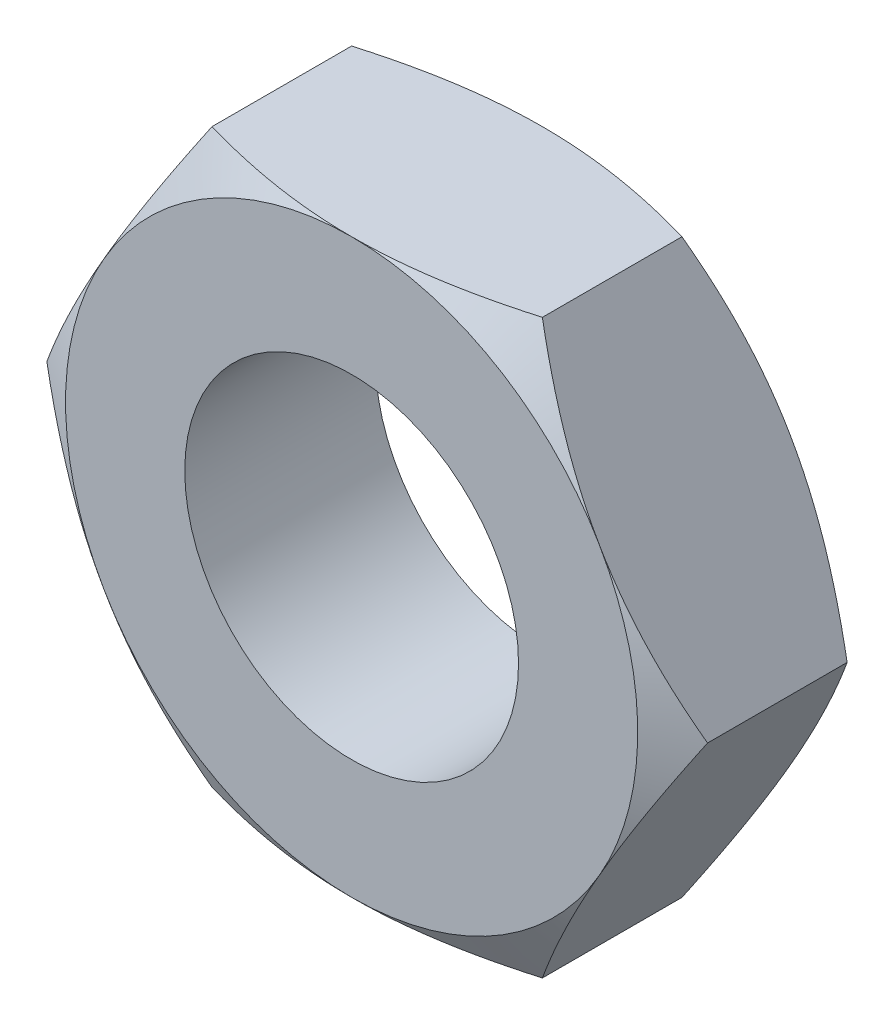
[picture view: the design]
ISO-10303-21;
HEADER;
FILE_DESCRIPTION(('STEP AP214'),'2;1');
FILE_NAME('part.step','',(''),(''),'','','');
FILE_SCHEMA(('AUTOMOTIVE_DESIGN { 1 0 10303 214 1 1 1 1 }'));
ENDSEC;
DATA;
#1=APPLICATION_CONTEXT('core data for automotive mechanical design processes');
#2=APPLICATION_PROTOCOL_DEFINITION('international standard','automotive_design',2000,#1);
#3=PRODUCT_CONTEXT('',#1,'mechanical');
#4=PRODUCT('Part','Part','',(#3));
#5=PRODUCT_RELATED_PRODUCT_CATEGORY('part','',(#4));
#6=PRODUCT_DEFINITION_FORMATION('','',#4);
#7=PRODUCT_DEFINITION_CONTEXT('part definition',#1,'design');
#8=PRODUCT_DEFINITION('design','',#6,#7);
#9=PRODUCT_DEFINITION_SHAPE('','',#8);
#10=(LENGTH_UNIT() NAMED_UNIT(*) SI_UNIT(.MILLI.,.METRE.));
#11=(NAMED_UNIT(*) PLANE_ANGLE_UNIT() SI_UNIT($,.RADIAN.));
#12=(NAMED_UNIT(*) SI_UNIT($,.STERADIAN.) SOLID_ANGLE_UNIT());
#13=UNCERTAINTY_MEASURE_WITH_UNIT(LENGTH_MEASURE(1.E-05),#10,'distance_accuracy_value','');
#14=(GEOMETRIC_REPRESENTATION_CONTEXT(3) GLOBAL_UNCERTAINTY_ASSIGNED_CONTEXT((#13)) GLOBAL_UNIT_ASSIGNED_CONTEXT((#10,
#11,#12)) REPRESENTATION_CONTEXT('',''));
#15=CARTESIAN_POINT('',(0.,0.,0.));
#16=DIRECTION('',(0.,0.,1.));
#17=DIRECTION('',(1.,0.,0.));
#18=AXIS2_PLACEMENT_3D('',#15,#16,#17);
#19=CARTESIAN_POINT('',(13.856406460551,0.,4.));
#20=DIRECTION('',(-0.866025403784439,-0.5,0.));
#21=DIRECTION('',(0.5,-0.866025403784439,0.));
#22=AXIS2_PLACEMENT_3D('',#19,#20,#21);
#23=PLANE('',#22);
#24=CARTESIAN_POINT('',(6.92808776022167,12.0002,-2.92813656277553));
#25=CARTESIAN_POINT('',(7.08038456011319,11.7364142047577,-3.01605036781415));
#26=CARTESIAN_POINT('',(7.23324920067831,11.4716448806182,-3.09997400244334));
#27=CARTESIAN_POINT('',(7.54020434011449,10.9399829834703,-3.25873378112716));
#28=CARTESIAN_POINT('',(7.69429522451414,10.6730897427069,-3.33356693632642));
#29=CARTESIAN_POINT('',(8.15905073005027,9.86810959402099,-3.54298246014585));
#30=CARTESIAN_POINT('',(8.47155003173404,9.3268449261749,-3.66209676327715));
#31=CARTESIAN_POINT('',(8.93919090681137,8.51686717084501,-3.80176893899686));
#32=CARTESIAN_POINT('',(9.09293539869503,8.25057389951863,-3.84155620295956));
#33=CARTESIAN_POINT('',(9.40113622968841,7.71675440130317,-3.90827663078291));
#34=CARTESIAN_POINT('',(9.55559258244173,7.44922815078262,-3.93520954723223));
#35=CARTESIAN_POINT('',(9.86476279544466,6.91372963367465,-3.97553140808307));
#36=CARTESIAN_POINT('',(10.0194761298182,6.64575827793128,-3.98893644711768));
#37=CARTESIAN_POINT('',(10.3290461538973,6.10956726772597,-4.00191690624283));
#38=CARTESIAN_POINT('',(10.4839028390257,5.84134762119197,-4.00149275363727));
#39=CARTESIAN_POINT('',(10.7734076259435,5.3399106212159,-3.98777998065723));
#40=CARTESIAN_POINT('',(10.908076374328,5.10665750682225,-3.97616401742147));
#41=CARTESIAN_POINT('',(11.1771041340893,4.64068775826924,-3.94269199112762));
#42=CARTESIAN_POINT('',(11.3114631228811,4.40797116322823,-3.92083520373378));
#43=CARTESIAN_POINT('',(11.5797983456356,3.94320092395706,-3.86726258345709));
#44=CARTESIAN_POINT('',(11.7137741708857,3.711147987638,-3.83553860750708));
#45=CARTESIAN_POINT('',(11.9810977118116,3.24813003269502,-3.76278822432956));
#46=CARTESIAN_POINT('',(12.1144453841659,3.01716508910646,-3.7217611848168));
#47=CARTESIAN_POINT('',(12.5192297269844,2.31605804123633,-3.5836883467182));
#48=CARTESIAN_POINT('',(12.789494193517,1.84794625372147,-3.47287511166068));
#49=CARTESIAN_POINT('',(13.3259930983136,0.918702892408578,-3.22137423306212));
#50=CARTESIAN_POINT('',(13.5922344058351,0.457559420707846,-3.08074565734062));
#51=CARTESIAN_POINT('',(13.8565219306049,-0.000200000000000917,-2.92813656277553));
#52=B_SPLINE_CURVE_WITH_KNOTS('',3,(#24,#25,#26,#27,#28,#29,#30,#31,#32,#33,#34,#35,#36,#37,#38,
#39,#40,#41,#42,#43,#44,#45,#46,#47,#48,#49,#50,#51),.UNSPECIFIED.,.F.,.F.,(4,2,2,2,2,2,2,2,2,2,
2,2,2,4),(0.,0.951004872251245,1.90232158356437,3.80900466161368,4.7389455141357,
5.66890426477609,6.59775529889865,7.52657763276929,8.33514643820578,9.14377244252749,
9.95306755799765,10.7624176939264,12.4167102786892,14.0677556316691),.UNSPECIFIED.);
#53=CARTESIAN_POINT('',(6.92820323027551,12.,-2.92820323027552));
#54=VERTEX_POINT('',#53);
#55=CARTESIAN_POINT('',(10.3923048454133,6.,-4.));
#56=VERTEX_POINT('',#55);
#57=EDGE_CURVE('E127',#54,#56,#52,.T.);
#58=ORIENTED_EDGE('',*,*,#57,.F.);
#59=DIRECTION('',(0.,0.,-1.));
#60=VECTOR('',#59,1.);
#61=CARTESIAN_POINT('',(6.92820323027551,12.,4.));
#62=LINE('',#61,#60);
#63=CARTESIAN_POINT('',(6.92820323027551,12.,2.92820323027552));
#64=VERTEX_POINT('',#63);
#65=EDGE_CURVE('E264',#64,#54,#62,.T.);
#66=ORIENTED_EDGE('',*,*,#65,.F.);
#67=CARTESIAN_POINT('',(13.8565219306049,-0.000200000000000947,2.92813656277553));
#68=CARTESIAN_POINT('',(13.7042251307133,0.263585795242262,3.01605036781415));
#69=CARTESIAN_POINT('',(13.5513604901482,0.528355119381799,3.09997400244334));
#70=CARTESIAN_POINT('',(13.244405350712,1.06001701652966,3.25873378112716));
#71=CARTESIAN_POINT('',(13.0903144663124,1.32691025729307,3.33356693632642));
#72=CARTESIAN_POINT('',(12.6255589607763,2.13189040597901,3.54298246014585));
#73=CARTESIAN_POINT('',(12.3130596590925,2.6731550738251,3.66209676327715));
#74=CARTESIAN_POINT('',(11.8454187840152,3.48313282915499,3.80176893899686));
#75=CARTESIAN_POINT('',(11.6916742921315,3.74942610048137,3.84155620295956));
#76=CARTESIAN_POINT('',(11.3834734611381,4.28324559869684,3.90827663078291));
#77=CARTESIAN_POINT('',(11.2290171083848,4.55077184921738,3.93520954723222));
#78=CARTESIAN_POINT('',(10.9198468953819,5.08627036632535,3.97553140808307));
#79=CARTESIAN_POINT('',(10.7651335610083,5.35424172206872,3.98893644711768));
#80=CARTESIAN_POINT('',(10.4555635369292,5.89043273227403,4.00191690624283));
#81=CARTESIAN_POINT('',(10.3007068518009,6.15865237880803,4.00149275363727));
#82=CARTESIAN_POINT('',(10.0112020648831,6.6600893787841,3.98777998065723));
#83=CARTESIAN_POINT('',(9.87653331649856,6.89334249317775,3.97616401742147));
#84=CARTESIAN_POINT('',(9.60750555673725,7.35931224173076,3.94269199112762));
#85=CARTESIAN_POINT('',(9.47314656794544,7.59202883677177,3.92083520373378));
#86=CARTESIAN_POINT('',(9.2048113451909,8.05679907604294,3.86726258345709));
#87=CARTESIAN_POINT('',(9.07083551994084,8.288852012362,3.83553860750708));
#88=CARTESIAN_POINT('',(8.80351197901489,8.75186996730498,3.76278822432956));
#89=CARTESIAN_POINT('',(8.67016430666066,8.98283491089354,3.7217611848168));
#90=CARTESIAN_POINT('',(8.2653799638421,9.68394195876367,3.5836883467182));
#91=CARTESIAN_POINT('',(7.99511549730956,10.1520537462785,3.47287511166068));
#92=CARTESIAN_POINT('',(7.45861659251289,11.0812971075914,3.22137423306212));
#93=CARTESIAN_POINT('',(7.19237528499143,11.5424405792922,3.08074565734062));
#94=CARTESIAN_POINT('',(6.92808776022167,12.0002,2.92813656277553));
#95=B_SPLINE_CURVE_WITH_KNOTS('',3,(#67,#68,#69,#70,#71,#72,#73,#74,#75,#76,#77,#78,#79,#80,#81,
#82,#83,#84,#85,#86,#87,#88,#89,#90,#91,#92,#93,#94),.UNSPECIFIED.,.F.,.F.,(4,2,2,2,2,2,2,2,2,2,
2,2,2,4),(0.,0.951004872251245,1.90232158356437,3.80900466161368,4.7389455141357,
5.66890426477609,6.59775529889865,7.5265776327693,8.33514643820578,9.14377244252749,
9.95306755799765,10.7624176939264,12.4167102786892,14.0677556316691),.UNSPECIFIED.);
#96=CARTESIAN_POINT('',(10.3923048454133,6.,4.));
#97=VERTEX_POINT('',#96);
#98=EDGE_CURVE('E240',#97,#64,#95,.T.);
#99=ORIENTED_EDGE('',*,*,#98,.F.);
#100=CARTESIAN_POINT('',(13.856406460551,0.,2.92820323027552));
#101=VERTEX_POINT('',#100);
#102=EDGE_CURVE('E246',#101,#97,#95,.T.);
#103=ORIENTED_EDGE('',*,*,#102,.F.);
#104=DIRECTION('',(0.,0.,-1.));
#105=VECTOR('',#104,1.);
#106=CARTESIAN_POINT('',(13.856406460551,0.,4.));
#107=LINE('',#106,#105);
#108=CARTESIAN_POINT('',(13.856406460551,0.,-2.92820323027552));
#109=VERTEX_POINT('',#108);
#110=EDGE_CURVE('E163',#101,#109,#107,.T.);
#111=ORIENTED_EDGE('',*,*,#110,.T.);
#112=EDGE_CURVE('E141',#56,#109,#52,.T.);
#113=ORIENTED_EDGE('',*,*,#112,.F.);
#114=EDGE_LOOP('',(#58,#66,#99,#103,#111,#113));
#115=FACE_BOUND('',#114,.T.);
#116=ADVANCED_FACE('F37',(#115),#23,.F.);
#117=CARTESIAN_POINT('',(6.92820323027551,12.,4.));
#118=DIRECTION('',(0.,-1.,0.));
#119=DIRECTION('',(1.,0.,0.));
#120=AXIS2_PLACEMENT_3D('',#117,#118,#119);
#121=PLANE('',#120);
#122=CARTESIAN_POINT('',(-18.7085127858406,12.,1.90415756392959));
#123=CARTESIAN_POINT('',(-18.4460090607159,12.,1.77659054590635));
#124=CARTESIAN_POINT('',(-18.1831999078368,12.,1.64965232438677));
#125=CARTESIAN_POINT('',(-17.6569070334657,12.,1.39717571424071));
#126=CARTESIAN_POINT('',(-17.3934233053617,12.,1.27163733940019));
#127=CARTESIAN_POINT('',(-16.6017958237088,12.,0.897302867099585));
#128=CARTESIAN_POINT('',(-16.0725519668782,12.,0.650824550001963));
#129=CARTESIAN_POINT('',(-15.007722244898,12.,0.164215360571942));
#130=CARTESIAN_POINT('',(-14.4721175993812,12.,-0.0758745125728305));
#131=CARTESIAN_POINT('',(-13.3966823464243,12.,-0.546361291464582));
#132=CARTESIAN_POINT('',(-12.8568519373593,12.,-0.776758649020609));
#133=CARTESIAN_POINT('',(-11.7544580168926,12.,-1.23259581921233));
#134=CARTESIAN_POINT('',(-11.1917261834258,12.,-1.45763065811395));
#135=CARTESIAN_POINT('',(-10.0597119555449,12.,-1.8909069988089));
#136=CARTESIAN_POINT('',(-9.49042883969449,12.,-2.09914663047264));
#137=CARTESIAN_POINT('',(-8.34545795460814,12.,-2.49343583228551));
#138=CARTESIAN_POINT('',(-7.76978547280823,12.,-2.67952944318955));
#139=CARTESIAN_POINT('',(-6.61012992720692,12.,-3.023632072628));
#140=CARTESIAN_POINT('',(-6.02614951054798,12.,-3.1816498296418));
#141=CARTESIAN_POINT('',(-5.14541828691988,12.,-3.3915280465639));
#142=CARTESIAN_POINT('',(-4.85184995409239,12.,-3.45682212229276));
#143=CARTESIAN_POINT('',(-4.26268919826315,12.,-3.57758690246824));
#144=CARTESIAN_POINT('',(-3.96709681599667,12.,-3.63305780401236));
#145=CARTESIAN_POINT('',(-3.37408559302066,12.,-3.73320305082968));
#146=CARTESIAN_POINT('',(-3.07666678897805,12.,-3.77787761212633));
#147=CARTESIAN_POINT('',(-2.48030879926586,12.,-3.85554301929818));
#148=CARTESIAN_POINT('',(-2.18136967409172,12.,-3.88853432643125));
#149=CARTESIAN_POINT('',(-1.58633736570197,12.,-3.94175838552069));
#150=CARTESIAN_POINT('',(-1.29025885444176,12.,-3.96215415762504));
#151=CARTESIAN_POINT('',(-0.697504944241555,12.,-3.99040145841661));
#152=CARTESIAN_POINT('',(-0.400829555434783,12.,-3.9982531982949));
#153=CARTESIAN_POINT('',(0.192590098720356,12.,-4.00122522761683));
#154=CARTESIAN_POINT('',(0.489334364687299,12.,-3.99634539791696));
#155=CARTESIAN_POINT('',(1.08235044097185,12.,-3.97397458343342));
#156=CARTESIAN_POINT('',(1.37862222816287,12.,-3.95648299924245));
#157=CARTESIAN_POINT('',(2.08755229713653,12.,-3.89991202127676));
#158=CARTESIAN_POINT('',(2.49975691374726,12.,-3.85502143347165));
#159=CARTESIAN_POINT('',(3.32115295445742,12.,-3.74325294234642));
#160=CARTESIAN_POINT('',(3.73034397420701,12.,-3.676372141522));
#161=CARTESIAN_POINT('',(4.95289147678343,12.,-3.44628715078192));
#162=CARTESIAN_POINT('',(5.76078996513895,12.,-3.25367949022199));
#163=CARTESIAN_POINT('',(6.96921318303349,12.,-2.91902105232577));
#164=CARTESIAN_POINT('',(7.37598411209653,12.,-2.79822311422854));
#165=CARTESIAN_POINT('',(8.18557519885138,12.,-2.54392558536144));
#166=CARTESIAN_POINT('',(8.58839532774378,12.,-2.41042590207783));
#167=CARTESIAN_POINT('',(9.39021237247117,12.,-2.13288017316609));
#168=CARTESIAN_POINT('',(9.78921043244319,12.,-1.98883740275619));
#169=CARTESIAN_POINT('',(10.5838863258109,12.,-1.69191619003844));
#170=CARTESIAN_POINT('',(10.9795642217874,12.,-1.53903791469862));
#171=CARTESIAN_POINT('',(12.0030149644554,12.,-1.13257010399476));
#172=CARTESIAN_POINT('',(12.6285198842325,12.,-0.873276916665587));
#173=CARTESIAN_POINT('',(13.8734735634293,12.,-0.340490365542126));
#174=CARTESIAN_POINT('',(14.4929217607,12.,-0.0669956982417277));
#175=CARTESIAN_POINT('',(15.7270740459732,12.,0.490985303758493));
#176=CARTESIAN_POINT('',(16.3417765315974,12.,0.775475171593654));
#177=CARTESIAN_POINT('',(17.5671457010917,12.,1.35294000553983));
#178=CARTESIAN_POINT('',(18.1778125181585,12.,1.6459146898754));
#179=CARTESIAN_POINT('',(19.3967367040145,12.,2.23899938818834));
#180=CARTESIAN_POINT('',(20.0049894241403,12.,2.53911893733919));
#181=CARTESIAN_POINT('',(21.218803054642,12.,3.14475459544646));
#182=CARTESIAN_POINT('',(21.8243639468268,12.,3.45027074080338));
#183=CARTESIAN_POINT('',(23.0331444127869,12.,4.06562299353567));
#184=CARTESIAN_POINT('',(23.636364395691,12.,4.37545829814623));
#185=CARTESIAN_POINT('',(24.8409400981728,12.,4.99872415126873));
#186=CARTESIAN_POINT('',(25.4422958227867,12.,5.31215469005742));
#187=CARTESIAN_POINT('',(27.1254633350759,12.,6.19473158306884));
#188=CARTESIAN_POINT('',(28.2055235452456,12.,6.7672178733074));
#189=CARTESIAN_POINT('',(30.3619311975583,12.,7.91925803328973));
#190=CARTESIAN_POINT('',(31.4382784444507,12.,8.49881226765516));
#191=CARTESIAN_POINT('',(33.584834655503,12.,9.66146627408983));
#192=CARTESIAN_POINT('',(34.6550523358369,12.,10.2445499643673));
#193=CARTESIAN_POINT('',(36.2586680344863,12.,11.1222102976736));
#194=CARTESIAN_POINT('',(36.7929031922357,12.,11.4152594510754));
#195=CARTESIAN_POINT('',(37.8608740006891,12.,12.0022649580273));
#196=CARTESIAN_POINT('',(38.3946096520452,12.,12.2962213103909));
#197=CARTESIAN_POINT('',(38.9281254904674,12.,12.5905761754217));
#198=B_SPLINE_CURVE_WITH_KNOTS('',3,(#122,#123,#124,#125,#126,#127,#128,#129,#130,#131,#132,
#133,#134,#135,#136,#137,#138,#139,#140,#141,#142,#143,#144,#145,#146,#147,#148,#149,#150,#151,
#152,#153,#154,#155,#156,#157,#158,#159,#160,#161,#162,#163,#164,#165,#166,#167,#168,#169,#170,
#171,#172,#173,#174,#175,#176,#177,#178,#179,#180,#181,#182,#183,#184,#185,#186,#187,#188,#189,
#190,#191,#192,#193,#194,#195,#196,#197),.UNSPECIFIED.,.F.,.F.,(4,2,2,2,2,2,2,2,2,2,2,2,2,2,2,2,
2,2,2,2,2,2,2,2,2,2,2,2,2,2,2,2,2,2,2,2,2,4),(0.,0.875574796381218,1.7511582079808,
3.50257929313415,5.2633676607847,7.02407385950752,8.84204683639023,10.6602219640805,
12.4747187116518,14.2886497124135,15.190737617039,16.0928074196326,16.9948591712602,
17.8968753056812,18.7869578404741,19.6770253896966,20.5671012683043,21.4572194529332,
22.7004447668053,23.9438339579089,26.4319090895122,27.7047859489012,28.9776720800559,
30.2501644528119,31.5226327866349,33.5537333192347,35.5850206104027,37.6169661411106,
39.648844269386,41.6836056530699,43.7183807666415,45.7527826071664,47.7871789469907,
51.4543492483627,55.1217095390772,58.7779483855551,60.6059425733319,62.4339343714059),.UNSPECIFIED.);
#199=CARTESIAN_POINT('',(-6.92820323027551,12.,-2.92820323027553));
#200=VERTEX_POINT('',#199);
#201=CARTESIAN_POINT('',(0.,12.,-4.));
#202=VERTEX_POINT('',#201);
#203=EDGE_CURVE('E53',#200,#202,#198,.T.);
#204=ORIENTED_EDGE('',*,*,#203,.F.);
#205=DIRECTION('',(0.,0.,-1.));
#206=VECTOR('',#205,1.);
#207=CARTESIAN_POINT('',(-6.92820323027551,12.,4.));
#208=LINE('',#207,#206);
#209=CARTESIAN_POINT('',(-6.92820323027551,12.,2.92820323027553));
#210=VERTEX_POINT('',#209);
#211=EDGE_CURVE('E260',#210,#200,#208,.T.);
#212=ORIENTED_EDGE('',*,*,#211,.F.);
#213=CARTESIAN_POINT('',(-18.7085127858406,12.,-1.90415756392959));
#214=CARTESIAN_POINT('',(-18.4460090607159,12.,-1.77659054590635));
#215=CARTESIAN_POINT('',(-18.1831999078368,12.,-1.64965232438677));
#216=CARTESIAN_POINT('',(-17.6569070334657,12.,-1.39717571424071));
#217=CARTESIAN_POINT('',(-17.3934233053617,12.,-1.27163733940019));
#218=CARTESIAN_POINT('',(-16.6017958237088,12.,-0.897302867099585));
#219=CARTESIAN_POINT('',(-16.0725519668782,12.,-0.650824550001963));
#220=CARTESIAN_POINT('',(-15.007722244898,12.,-0.164215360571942));
#221=CARTESIAN_POINT('',(-14.4721175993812,12.,0.0758745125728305));
#222=CARTESIAN_POINT('',(-13.3966823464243,12.,0.546361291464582));
#223=CARTESIAN_POINT('',(-12.8568519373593,12.,0.776758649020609));
#224=CARTESIAN_POINT('',(-11.7544580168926,12.,1.23259581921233));
#225=CARTESIAN_POINT('',(-11.1917261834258,12.,1.45763065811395));
#226=CARTESIAN_POINT('',(-10.0597119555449,12.,1.8909069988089));
#227=CARTESIAN_POINT('',(-9.49042883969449,12.,2.09914663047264));
#228=CARTESIAN_POINT('',(-8.34545795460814,12.,2.49343583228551));
#229=CARTESIAN_POINT('',(-7.76978547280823,12.,2.67952944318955));
#230=CARTESIAN_POINT('',(-6.61012992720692,12.,3.023632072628));
#231=CARTESIAN_POINT('',(-6.02614951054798,12.,3.1816498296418));
#232=CARTESIAN_POINT('',(-5.14541828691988,12.,3.3915280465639));
#233=CARTESIAN_POINT('',(-4.85184995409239,12.,3.45682212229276));
#234=CARTESIAN_POINT('',(-4.26268919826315,12.,3.57758690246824));
#235=CARTESIAN_POINT('',(-3.96709681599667,12.,3.63305780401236));
#236=CARTESIAN_POINT('',(-3.37408559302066,12.,3.73320305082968));
#237=CARTESIAN_POINT('',(-3.07666678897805,12.,3.77787761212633));
#238=CARTESIAN_POINT('',(-2.48030879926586,12.,3.85554301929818));
#239=CARTESIAN_POINT('',(-2.18136967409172,12.,3.88853432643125));
#240=CARTESIAN_POINT('',(-1.58633736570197,12.,3.94175838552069));
#241=CARTESIAN_POINT('',(-1.29025885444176,12.,3.96215415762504));
#242=CARTESIAN_POINT('',(-0.697504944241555,12.,3.99040145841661));
#243=CARTESIAN_POINT('',(-0.400829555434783,12.,3.9982531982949));
#244=CARTESIAN_POINT('',(0.192590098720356,12.,4.00122522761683));
#245=CARTESIAN_POINT('',(0.489334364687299,12.,3.99634539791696));
#246=CARTESIAN_POINT('',(1.08235044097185,12.,3.97397458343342));
#247=CARTESIAN_POINT('',(1.37862222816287,12.,3.95648299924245));
#248=CARTESIAN_POINT('',(2.08755229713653,12.,3.89991202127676));
#249=CARTESIAN_POINT('',(2.49975691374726,12.,3.85502143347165));
#250=CARTESIAN_POINT('',(3.32115295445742,12.,3.74325294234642));
#251=CARTESIAN_POINT('',(3.73034397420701,12.,3.676372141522));
#252=CARTESIAN_POINT('',(4.95289147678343,12.,3.44628715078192));
#253=CARTESIAN_POINT('',(5.76078996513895,12.,3.25367949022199));
#254=CARTESIAN_POINT('',(6.96921318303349,12.,2.91902105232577));
#255=CARTESIAN_POINT('',(7.37598411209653,12.,2.79822311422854));
#256=CARTESIAN_POINT('',(8.18557519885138,12.,2.54392558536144));
#257=CARTESIAN_POINT('',(8.58839532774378,12.,2.41042590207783));
#258=CARTESIAN_POINT('',(9.39021237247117,12.,2.13288017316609));
#259=CARTESIAN_POINT('',(9.78921043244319,12.,1.98883740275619));
#260=CARTESIAN_POINT('',(10.5838863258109,12.,1.69191619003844));
#261=CARTESIAN_POINT('',(10.9795642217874,12.,1.53903791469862));
#262=CARTESIAN_POINT('',(12.0030149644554,12.,1.13257010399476));
#263=CARTESIAN_POINT('',(12.6285198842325,12.,0.873276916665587));
#264=CARTESIAN_POINT('',(13.8734735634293,12.,0.340490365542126));
#265=CARTESIAN_POINT('',(14.4929217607,12.,0.0669956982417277));
#266=CARTESIAN_POINT('',(15.7270740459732,12.,-0.490985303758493));
#267=CARTESIAN_POINT('',(16.3417765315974,12.,-0.775475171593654));
#268=CARTESIAN_POINT('',(17.5671457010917,12.,-1.35294000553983));
#269=CARTESIAN_POINT('',(18.1778125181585,12.,-1.6459146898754));
#270=CARTESIAN_POINT('',(19.3967367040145,12.,-2.23899938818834));
#271=CARTESIAN_POINT('',(20.0049894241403,12.,-2.53911893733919));
#272=CARTESIAN_POINT('',(21.218803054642,12.,-3.14475459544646));
#273=CARTESIAN_POINT('',(21.8243639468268,12.,-3.45027074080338));
#274=CARTESIAN_POINT('',(23.0331444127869,12.,-4.06562299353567));
#275=CARTESIAN_POINT('',(23.636364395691,12.,-4.37545829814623));
#276=CARTESIAN_POINT('',(24.8409400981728,12.,-4.99872415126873));
#277=CARTESIAN_POINT('',(25.4422958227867,12.,-5.31215469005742));
#278=CARTESIAN_POINT('',(27.1254633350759,12.,-6.19473158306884));
#279=CARTESIAN_POINT('',(28.2055235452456,12.,-6.7672178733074));
#280=CARTESIAN_POINT('',(30.3619311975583,12.,-7.91925803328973));
#281=CARTESIAN_POINT('',(31.4382784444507,12.,-8.49881226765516));
#282=CARTESIAN_POINT('',(33.584834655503,12.,-9.66146627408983));
#283=CARTESIAN_POINT('',(34.6550523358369,12.,-10.2445499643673));
#284=CARTESIAN_POINT('',(36.2586680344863,12.,-11.1222102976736));
#285=CARTESIAN_POINT('',(36.7929031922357,12.,-11.4152594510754));
#286=CARTESIAN_POINT('',(37.8608740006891,12.,-12.0022649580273));
#287=CARTESIAN_POINT('',(38.3946096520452,12.,-12.2962213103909));
#288=CARTESIAN_POINT('',(38.9281254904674,12.,-12.5905761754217));
#289=B_SPLINE_CURVE_WITH_KNOTS('',3,(#213,#214,#215,#216,#217,#218,#219,#220,#221,#222,#223,
#224,#225,#226,#227,#228,#229,#230,#231,#232,#233,#234,#235,#236,#237,#238,#239,#240,#241,#242,
#243,#244,#245,#246,#247,#248,#249,#250,#251,#252,#253,#254,#255,#256,#257,#258,#259,#260,#261,
#262,#263,#264,#265,#266,#267,#268,#269,#270,#271,#272,#273,#274,#275,#276,#277,#278,#279,#280,
#281,#282,#283,#284,#285,#286,#287,#288),.UNSPECIFIED.,.F.,.F.,(4,2,2,2,2,2,2,2,2,2,2,2,2,2,2,2,
2,2,2,2,2,2,2,2,2,2,2,2,2,2,2,2,2,2,2,2,2,4),(0.,0.875574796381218,1.7511582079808,
3.50257929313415,5.2633676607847,7.02407385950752,8.84204683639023,10.6602219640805,
12.4747187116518,14.2886497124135,15.190737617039,16.0928074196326,16.9948591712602,
17.8968753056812,18.7869578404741,19.6770253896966,20.5671012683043,21.4572194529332,
22.7004447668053,23.9438339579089,26.4319090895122,27.7047859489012,28.9776720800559,
30.2501644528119,31.5226327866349,33.5537333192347,35.5850206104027,37.6169661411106,
39.648844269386,41.6836056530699,43.7183807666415,45.7527826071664,47.7871789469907,
51.4543492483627,55.1217095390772,58.7779483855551,60.6059425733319,62.4339343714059),.UNSPECIFIED.);
#290=CARTESIAN_POINT('',(0.,12.,4.));
#291=VERTEX_POINT('',#290);
#292=EDGE_CURVE('E226',#291,#210,#289,.F.);
#293=ORIENTED_EDGE('',*,*,#292,.F.);
#294=EDGE_CURVE('E233',#64,#291,#289,.F.);
#295=ORIENTED_EDGE('',*,*,#294,.F.);
#296=ORIENTED_EDGE('',*,*,#65,.T.);
#297=EDGE_CURVE('E134',#202,#54,#198,.T.);
#298=ORIENTED_EDGE('',*,*,#297,.F.);
#299=EDGE_LOOP('',(#204,#212,#293,#295,#296,#298));
#300=FACE_BOUND('',#299,.T.);
#301=ADVANCED_FACE('F218',(#300),#121,.F.);
#302=CARTESIAN_POINT('',(-6.92820323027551,12.,4.));
#303=DIRECTION('',(0.866025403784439,-0.5,0.));
#304=DIRECTION('',(0.5,0.866025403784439,0.));
#305=AXIS2_PLACEMENT_3D('',#302,#303,#304);
#306=PLANE('',#305);
#307=CARTESIAN_POINT('',(-13.8565219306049,-0.000200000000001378,-2.92813656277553));
#308=CARTESIAN_POINT('',(-13.7042251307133,0.263585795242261,-3.01605036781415));
#309=CARTESIAN_POINT('',(-13.5513604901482,0.528355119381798,-3.09997400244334));
#310=CARTESIAN_POINT('',(-13.244405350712,1.06001701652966,-3.25873378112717));
#311=CARTESIAN_POINT('',(-13.0903144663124,1.32691025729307,-3.33356693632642));
#312=CARTESIAN_POINT('',(-12.6255589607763,2.13189040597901,-3.54298246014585));
#313=CARTESIAN_POINT('',(-12.3130596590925,2.6731550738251,-3.66209676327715));
#314=CARTESIAN_POINT('',(-11.8454187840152,3.48313282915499,-3.80176893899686));
#315=CARTESIAN_POINT('',(-11.6916742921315,3.74942610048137,-3.84155620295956));
#316=CARTESIAN_POINT('',(-11.3834734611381,4.28324559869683,-3.90827663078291));
#317=CARTESIAN_POINT('',(-11.2290171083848,4.55077184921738,-3.93520954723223));
#318=CARTESIAN_POINT('',(-10.9198468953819,5.08627036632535,-3.97553140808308));
#319=CARTESIAN_POINT('',(-10.7651335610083,5.35424172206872,-3.98893644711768));
#320=CARTESIAN_POINT('',(-10.4555635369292,5.89043273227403,-4.00191690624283));
#321=CARTESIAN_POINT('',(-10.3007068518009,6.15865237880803,-4.00149275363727));
#322=CARTESIAN_POINT('',(-10.011202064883,6.6600893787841,-3.98777998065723));
#323=CARTESIAN_POINT('',(-9.87653331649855,6.89334249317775,-3.97616401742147));
#324=CARTESIAN_POINT('',(-9.60750555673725,7.35931224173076,-3.94269199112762));
#325=CARTESIAN_POINT('',(-9.47314656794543,7.59202883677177,-3.92083520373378));
#326=CARTESIAN_POINT('',(-9.2048113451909,8.05679907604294,-3.86726258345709));
#327=CARTESIAN_POINT('',(-9.07083551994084,8.288852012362,-3.83553860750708));
#328=CARTESIAN_POINT('',(-8.80351197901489,8.75186996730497,-3.76278822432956));
#329=CARTESIAN_POINT('',(-8.67016430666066,8.98283491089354,-3.7217611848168));
#330=CARTESIAN_POINT('',(-8.2653799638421,9.68394195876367,-3.5836883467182));
#331=CARTESIAN_POINT('',(-7.99511549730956,10.1520537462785,-3.47287511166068));
#332=CARTESIAN_POINT('',(-7.45861659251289,11.0812971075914,-3.22137423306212));
#333=CARTESIAN_POINT('',(-7.19237528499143,11.5424405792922,-3.08074565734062));
#334=CARTESIAN_POINT('',(-6.92808776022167,12.0002,-2.92813656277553));
#335=B_SPLINE_CURVE_WITH_KNOTS('',3,(#307,#308,#309,#310,#311,#312,#313,#314,#315,#316,#317,
#318,#319,#320,#321,#322,#323,#324,#325,#326,#327,#328,#329,#330,#331,#332,#333,#334),
.UNSPECIFIED.,.F.,.F.,(4,2,2,2,2,2,2,2,2,2,2,2,2,4),(0.,0.951004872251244,1.90232158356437,
3.80900466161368,4.73894551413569,5.66890426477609,6.59775529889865,7.52657763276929,
8.33514643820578,9.14377244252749,9.95306755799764,10.7624176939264,12.4167102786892,
14.0677556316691),.UNSPECIFIED.);
#336=CARTESIAN_POINT('',(-13.856406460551,0.,-2.92820323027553));
#337=VERTEX_POINT('',#336);
#338=CARTESIAN_POINT('',(-10.3923048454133,6.,-4.));
#339=VERTEX_POINT('',#338);
#340=EDGE_CURVE('E61',#337,#339,#335,.T.);
#341=ORIENTED_EDGE('',*,*,#340,.F.);
#342=DIRECTION('',(0.,0.,-1.));
#343=VECTOR('',#342,1.);
#344=CARTESIAN_POINT('',(-13.856406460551,0.,4.));
#345=LINE('',#344,#343);
#346=CARTESIAN_POINT('',(-13.856406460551,0.,2.92820323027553));
#347=VERTEX_POINT('',#346);
#348=EDGE_CURVE('E256',#347,#337,#345,.T.);
#349=ORIENTED_EDGE('',*,*,#348,.F.);
#350=CARTESIAN_POINT('',(-6.92808776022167,12.0002,2.92813656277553));
#351=CARTESIAN_POINT('',(-7.08038456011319,11.7364142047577,3.01605036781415));
#352=CARTESIAN_POINT('',(-7.23324920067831,11.4716448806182,3.09997400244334));
#353=CARTESIAN_POINT('',(-7.54020434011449,10.9399829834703,3.25873378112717));
#354=CARTESIAN_POINT('',(-7.69429522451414,10.6730897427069,3.33356693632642));
#355=CARTESIAN_POINT('',(-8.15905073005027,9.86810959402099,3.54298246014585));
#356=CARTESIAN_POINT('',(-8.47155003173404,9.3268449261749,3.66209676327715));
#357=CARTESIAN_POINT('',(-8.93919090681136,8.51686717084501,3.80176893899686));
#358=CARTESIAN_POINT('',(-9.09293539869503,8.25057389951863,3.84155620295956));
#359=CARTESIAN_POINT('',(-9.4011362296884,7.71675440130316,3.90827663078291));
#360=CARTESIAN_POINT('',(-9.55559258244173,7.44922815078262,3.93520954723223));
#361=CARTESIAN_POINT('',(-9.86476279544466,6.91372963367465,3.97553140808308));
#362=CARTESIAN_POINT('',(-10.0194761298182,6.64575827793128,3.98893644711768));
#363=CARTESIAN_POINT('',(-10.3290461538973,6.10956726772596,4.00191690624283));
#364=CARTESIAN_POINT('',(-10.4839028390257,5.84134762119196,4.00149275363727));
#365=CARTESIAN_POINT('',(-10.7734076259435,5.3399106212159,3.98777998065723));
#366=CARTESIAN_POINT('',(-10.908076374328,5.10665750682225,3.97616401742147));
#367=CARTESIAN_POINT('',(-11.1771041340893,4.64068775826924,3.94269199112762));
#368=CARTESIAN_POINT('',(-11.3114631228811,4.40797116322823,3.92083520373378));
#369=CARTESIAN_POINT('',(-11.5797983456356,3.94320092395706,3.86726258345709));
#370=CARTESIAN_POINT('',(-11.7137741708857,3.711147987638,3.83553860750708));
#371=CARTESIAN_POINT('',(-11.9810977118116,3.24813003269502,3.76278822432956));
#372=CARTESIAN_POINT('',(-12.1144453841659,3.01716508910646,3.7217611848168));
#373=CARTESIAN_POINT('',(-12.5192297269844,2.31605804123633,3.5836883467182));
#374=CARTESIAN_POINT('',(-12.789494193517,1.84794625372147,3.47287511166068));
#375=CARTESIAN_POINT('',(-13.3259930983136,0.918702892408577,3.22137423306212));
#376=CARTESIAN_POINT('',(-13.5922344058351,0.457559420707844,3.08074565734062));
#377=CARTESIAN_POINT('',(-13.8565219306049,-0.000200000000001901,2.92813656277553));
#378=B_SPLINE_CURVE_WITH_KNOTS('',3,(#350,#351,#352,#353,#354,#355,#356,#357,#358,#359,#360,
#361,#362,#363,#364,#365,#366,#367,#368,#369,#370,#371,#372,#373,#374,#375,#376,#377),
.UNSPECIFIED.,.F.,.F.,(4,2,2,2,2,2,2,2,2,2,2,2,2,4),(0.,0.951004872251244,1.90232158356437,
3.80900466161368,4.7389455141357,5.66890426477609,6.59775529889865,7.52657763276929,
8.33514643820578,9.14377244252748,9.95306755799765,10.7624176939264,12.4167102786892,
14.0677556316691),.UNSPECIFIED.);
#379=CARTESIAN_POINT('',(-10.3923048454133,6.,4.));
#380=VERTEX_POINT('',#379);
#381=EDGE_CURVE('E235',#380,#347,#378,.T.);
#382=ORIENTED_EDGE('',*,*,#381,.F.);
#383=EDGE_CURVE('E234',#210,#380,#378,.T.);
#384=ORIENTED_EDGE('',*,*,#383,.F.);
#385=ORIENTED_EDGE('',*,*,#211,.T.);
#386=EDGE_CURVE('E212',#339,#200,#335,.T.);
#387=ORIENTED_EDGE('',*,*,#386,.F.);
#388=EDGE_LOOP('',(#341,#349,#382,#384,#385,#387));
#389=FACE_BOUND('',#388,.T.);
#390=ADVANCED_FACE('F221',(#389),#306,.F.);
#391=CARTESIAN_POINT('',(-13.856406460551,0.,4.));
#392=DIRECTION('',(0.866025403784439,0.5,0.));
#393=DIRECTION('',(-0.5,0.866025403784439,0.));
#394=AXIS2_PLACEMENT_3D('',#391,#392,#393);
#395=PLANE('',#394);
#396=CARTESIAN_POINT('',(-6.92808776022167,-12.0002,-2.92813656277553));
#397=CARTESIAN_POINT('',(-7.08038456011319,-11.7364142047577,-3.01605036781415));
#398=CARTESIAN_POINT('',(-7.2332492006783,-11.4716448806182,-3.09997400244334));
#399=CARTESIAN_POINT('',(-7.54020434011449,-10.9399829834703,-3.25873378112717));
#400=CARTESIAN_POINT('',(-7.69429522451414,-10.6730897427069,-3.33356693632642));
#401=CARTESIAN_POINT('',(-8.15905073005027,-9.86810959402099,-3.54298246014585));
#402=CARTESIAN_POINT('',(-8.47155003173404,-9.3268449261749,-3.66209676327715));
#403=CARTESIAN_POINT('',(-8.93919090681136,-8.51686717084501,-3.80176893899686));
#404=CARTESIAN_POINT('',(-9.09293539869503,-8.25057389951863,-3.84155620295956));
#405=CARTESIAN_POINT('',(-9.4011362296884,-7.71675440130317,-3.90827663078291));
#406=CARTESIAN_POINT('',(-9.55559258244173,-7.44922815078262,-3.93520954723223));
#407=CARTESIAN_POINT('',(-9.86476279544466,-6.91372963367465,-3.97553140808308));
#408=CARTESIAN_POINT('',(-10.0194761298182,-6.64575827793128,-3.98893644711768));
#409=CARTESIAN_POINT('',(-10.3290461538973,-6.10956726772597,-4.00191690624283));
#410=CARTESIAN_POINT('',(-10.4839028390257,-5.84134762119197,-4.00149275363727));
#411=CARTESIAN_POINT('',(-10.7734076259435,-5.3399106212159,-3.98777998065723));
#412=CARTESIAN_POINT('',(-10.908076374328,-5.10665750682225,-3.97616401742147));
#413=CARTESIAN_POINT('',(-11.1771041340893,-4.64068775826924,-3.94269199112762));
#414=CARTESIAN_POINT('',(-11.3114631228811,-4.40797116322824,-3.92083520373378));
#415=CARTESIAN_POINT('',(-11.5797983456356,-3.94320092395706,-3.86726258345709));
#416=CARTESIAN_POINT('',(-11.7137741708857,-3.711147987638,-3.83553860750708));
#417=CARTESIAN_POINT('',(-11.9810977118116,-3.24813003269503,-3.76278822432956));
#418=CARTESIAN_POINT('',(-12.1144453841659,-3.01716508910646,-3.7217611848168));
#419=CARTESIAN_POINT('',(-12.5192297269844,-2.31605804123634,-3.5836883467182));
#420=CARTESIAN_POINT('',(-12.789494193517,-1.84794625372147,-3.47287511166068));
#421=CARTESIAN_POINT('',(-13.3259930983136,-0.918702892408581,-3.22137423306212));
#422=CARTESIAN_POINT('',(-13.5922344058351,-0.457559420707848,-3.08074565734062));
#423=CARTESIAN_POINT('',(-13.8565219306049,0.000199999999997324,-2.92813656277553));
#424=B_SPLINE_CURVE_WITH_KNOTS('',3,(#396,#397,#398,#399,#400,#401,#402,#403,#404,#405,#406,
#407,#408,#409,#410,#411,#412,#413,#414,#415,#416,#417,#418,#419,#420,#421,#422,#423),
.UNSPECIFIED.,.F.,.F.,(4,2,2,2,2,2,2,2,2,2,2,2,2,4),(0.,0.951004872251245,1.90232158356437,
3.80900466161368,4.7389455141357,5.66890426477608,6.59775529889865,7.52657763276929,
8.33514643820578,9.14377244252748,9.95306755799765,10.7624176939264,12.4167102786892,
14.0677556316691),.UNSPECIFIED.);
#425=CARTESIAN_POINT('',(-6.92820323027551,-12.,-2.92820323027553));
#426=VERTEX_POINT('',#425);
#427=CARTESIAN_POINT('',(-10.3923048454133,-6.,-4.));
#428=VERTEX_POINT('',#427);
#429=EDGE_CURVE('E180',#426,#428,#424,.T.);
#430=ORIENTED_EDGE('',*,*,#429,.F.);
#431=DIRECTION('',(0.,0.,-1.));
#432=VECTOR('',#431,1.);
#433=CARTESIAN_POINT('',(-6.92820323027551,-12.,4.));
#434=LINE('',#433,#432);
#435=CARTESIAN_POINT('',(-6.92820323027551,-12.,2.92820323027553));
#436=VERTEX_POINT('',#435);
#437=EDGE_CURVE('E252',#436,#426,#434,.T.);
#438=ORIENTED_EDGE('',*,*,#437,.F.);
#439=CARTESIAN_POINT('',(-13.8565219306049,0.0001999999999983,2.92813656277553));
#440=CARTESIAN_POINT('',(-13.7042251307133,-0.263585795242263,3.01605036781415));
#441=CARTESIAN_POINT('',(-13.5513604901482,-0.528355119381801,3.09997400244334));
#442=CARTESIAN_POINT('',(-13.244405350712,-1.06001701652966,3.25873378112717));
#443=CARTESIAN_POINT('',(-13.0903144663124,-1.32691025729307,3.33356693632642));
#444=CARTESIAN_POINT('',(-12.6255589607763,-2.13189040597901,3.54298246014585));
#445=CARTESIAN_POINT('',(-12.3130596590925,-2.6731550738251,3.66209676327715));
#446=CARTESIAN_POINT('',(-11.8454187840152,-3.483132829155,3.80176893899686));
#447=CARTESIAN_POINT('',(-11.6916742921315,-3.74942610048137,3.84155620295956));
#448=CARTESIAN_POINT('',(-11.3834734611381,-4.28324559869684,3.90827663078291));
#449=CARTESIAN_POINT('',(-11.2290171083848,-4.55077184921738,3.93520954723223));
#450=CARTESIAN_POINT('',(-10.9198468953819,-5.08627036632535,3.97553140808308));
#451=CARTESIAN_POINT('',(-10.7651335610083,-5.35424172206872,3.98893644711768));
#452=CARTESIAN_POINT('',(-10.4555635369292,-5.89043273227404,4.00191690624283));
#453=CARTESIAN_POINT('',(-10.3007068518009,-6.15865237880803,4.00149275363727));
#454=CARTESIAN_POINT('',(-10.011202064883,-6.6600893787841,3.98777998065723));
#455=CARTESIAN_POINT('',(-9.87653331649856,-6.89334249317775,3.97616401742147));
#456=CARTESIAN_POINT('',(-9.60750555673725,-7.35931224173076,3.94269199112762));
#457=CARTESIAN_POINT('',(-9.47314656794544,-7.59202883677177,3.92083520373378));
#458=CARTESIAN_POINT('',(-9.2048113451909,-8.05679907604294,3.86726258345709));
#459=CARTESIAN_POINT('',(-9.07083551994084,-8.288852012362,3.83553860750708));
#460=CARTESIAN_POINT('',(-8.80351197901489,-8.75186996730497,3.76278822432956));
#461=CARTESIAN_POINT('',(-8.67016430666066,-8.98283491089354,3.7217611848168));
#462=CARTESIAN_POINT('',(-8.2653799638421,-9.68394195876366,3.5836883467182));
#463=CARTESIAN_POINT('',(-7.99511549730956,-10.1520537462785,3.47287511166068));
#464=CARTESIAN_POINT('',(-7.45861659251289,-11.0812971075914,3.22137423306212));
#465=CARTESIAN_POINT('',(-7.19237528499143,-11.5424405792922,3.08074565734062));
#466=CARTESIAN_POINT('',(-6.92808776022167,-12.0002,2.92813656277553));
#467=B_SPLINE_CURVE_WITH_KNOTS('',3,(#439,#440,#441,#442,#443,#444,#445,#446,#447,#448,#449,
#450,#451,#452,#453,#454,#455,#456,#457,#458,#459,#460,#461,#462,#463,#464,#465,#466),
.UNSPECIFIED.,.F.,.F.,(4,2,2,2,2,2,2,2,2,2,2,2,2,4),(0.,0.951004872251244,1.90232158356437,
3.80900466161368,4.7389455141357,5.66890426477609,6.59775529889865,7.52657763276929,
8.33514643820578,9.14377244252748,9.95306755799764,10.7624176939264,12.4167102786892,
14.0677556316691),.UNSPECIFIED.);
#468=CARTESIAN_POINT('',(-10.3923048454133,-6.,4.));
#469=VERTEX_POINT('',#468);
#470=EDGE_CURVE('E310',#469,#436,#467,.T.);
#471=ORIENTED_EDGE('',*,*,#470,.F.);
#472=EDGE_CURVE('E532',#347,#469,#467,.T.);
#473=ORIENTED_EDGE('',*,*,#472,.F.);
#474=ORIENTED_EDGE('',*,*,#348,.T.);
#475=EDGE_CURVE('E530',#428,#337,#424,.T.);
#476=ORIENTED_EDGE('',*,*,#475,.F.);
#477=EDGE_LOOP('',(#430,#438,#471,#473,#474,#476));
#478=FACE_BOUND('',#477,.T.);
#479=ADVANCED_FACE('F325',(#478),#395,.F.);
#480=CARTESIAN_POINT('',(-6.92820323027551,-12.,4.));
#481=DIRECTION('',(0.,1.,0.));
#482=DIRECTION('',(0.,0.,1.));
#483=AXIS2_PLACEMENT_3D('',#480,#481,#482);
#484=PLANE('',#483);
#485=CARTESIAN_POINT('',(-18.7085127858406,-12.,1.90415756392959));
#486=CARTESIAN_POINT('',(-18.4460090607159,-12.,1.77659054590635));
#487=CARTESIAN_POINT('',(-18.1831999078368,-12.,1.64965232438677));
#488=CARTESIAN_POINT('',(-17.6569070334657,-12.,1.39717571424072));
#489=CARTESIAN_POINT('',(-17.3934233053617,-12.,1.27163733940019));
#490=CARTESIAN_POINT('',(-16.6017958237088,-12.,0.897302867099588));
#491=CARTESIAN_POINT('',(-16.0725519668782,-12.,0.650824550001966));
#492=CARTESIAN_POINT('',(-15.007722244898,-12.,0.164215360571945));
#493=CARTESIAN_POINT('',(-14.4721175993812,-12.,-0.0758745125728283));
#494=CARTESIAN_POINT('',(-13.3966823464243,-12.,-0.546361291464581));
#495=CARTESIAN_POINT('',(-12.8568519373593,-12.,-0.776758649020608));
#496=CARTESIAN_POINT('',(-11.7544580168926,-12.,-1.23259581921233));
#497=CARTESIAN_POINT('',(-11.1917261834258,-12.,-1.45763065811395));
#498=CARTESIAN_POINT('',(-10.0597119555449,-12.,-1.89090699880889));
#499=CARTESIAN_POINT('',(-9.49042883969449,-12.,-2.09914663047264));
#500=CARTESIAN_POINT('',(-8.34545795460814,-12.,-2.49343583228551));
#501=CARTESIAN_POINT('',(-7.76978547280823,-12.,-2.67952944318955));
#502=CARTESIAN_POINT('',(-6.61012992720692,-12.,-3.023632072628));
#503=CARTESIAN_POINT('',(-6.02614951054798,-12.,-3.1816498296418));
#504=CARTESIAN_POINT('',(-5.14541828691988,-12.,-3.3915280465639));
#505=CARTESIAN_POINT('',(-4.85184995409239,-12.,-3.45682212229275));
#506=CARTESIAN_POINT('',(-4.26268919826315,-12.,-3.57758690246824));
#507=CARTESIAN_POINT('',(-3.96709681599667,-12.,-3.63305780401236));
#508=CARTESIAN_POINT('',(-3.37408559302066,-12.,-3.73320305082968));
#509=CARTESIAN_POINT('',(-3.07666678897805,-12.,-3.77787761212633));
#510=CARTESIAN_POINT('',(-2.48030879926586,-12.,-3.85554301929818));
#511=CARTESIAN_POINT('',(-2.18136967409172,-12.,-3.88853432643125));
#512=CARTESIAN_POINT('',(-1.58633736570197,-12.,-3.9417583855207));
#513=CARTESIAN_POINT('',(-1.29025885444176,-12.,-3.96215415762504));
#514=CARTESIAN_POINT('',(-0.697504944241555,-12.,-3.99040145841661));
#515=CARTESIAN_POINT('',(-0.400829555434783,-12.,-3.9982531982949));
#516=CARTESIAN_POINT('',(0.192590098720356,-12.,-4.00122522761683));
#517=CARTESIAN_POINT('',(0.489334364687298,-12.,-3.99634539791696));
#518=CARTESIAN_POINT('',(1.08235044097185,-12.,-3.97397458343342));
#519=CARTESIAN_POINT('',(1.37862222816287,-12.,-3.95648299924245));
#520=CARTESIAN_POINT('',(2.08755229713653,-12.,-3.89991202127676));
#521=CARTESIAN_POINT('',(2.49975691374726,-12.,-3.85502143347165));
#522=CARTESIAN_POINT('',(3.32115295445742,-12.,-3.74325294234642));
#523=CARTESIAN_POINT('',(3.73034397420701,-12.,-3.676372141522));
#524=CARTESIAN_POINT('',(4.95289147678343,-12.,-3.44628715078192));
#525=CARTESIAN_POINT('',(5.76078996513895,-12.,-3.25367949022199));
#526=CARTESIAN_POINT('',(6.96921318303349,-12.,-2.91902105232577));
#527=CARTESIAN_POINT('',(7.37598411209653,-12.,-2.79822311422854));
#528=CARTESIAN_POINT('',(8.18557519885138,-12.,-2.54392558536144));
#529=CARTESIAN_POINT('',(8.58839532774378,-12.,-2.41042590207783));
#530=CARTESIAN_POINT('',(9.39021237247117,-12.,-2.13288017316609));
#531=CARTESIAN_POINT('',(9.7892104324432,-12.,-1.98883740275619));
#532=CARTESIAN_POINT('',(10.5838863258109,-12.,-1.69191619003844));
#533=CARTESIAN_POINT('',(10.9795642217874,-12.,-1.53903791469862));
#534=CARTESIAN_POINT('',(12.0030149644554,-12.,-1.13257010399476));
#535=CARTESIAN_POINT('',(12.6285198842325,-12.,-0.873276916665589));
#536=CARTESIAN_POINT('',(13.8734735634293,-12.,-0.340490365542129));
#537=CARTESIAN_POINT('',(14.4929217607,-12.,-0.0669956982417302));
#538=CARTESIAN_POINT('',(15.7270740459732,-12.,0.490985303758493));
#539=CARTESIAN_POINT('',(16.3417765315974,-12.,0.775475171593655));
#540=CARTESIAN_POINT('',(17.5671457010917,-12.,1.35294000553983));
#541=CARTESIAN_POINT('',(18.1778125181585,-12.,1.6459146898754));
#542=CARTESIAN_POINT('',(19.3967367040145,-12.,2.23899938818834));
#543=CARTESIAN_POINT('',(20.0049894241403,-12.,2.53911893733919));
#544=CARTESIAN_POINT('',(21.218803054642,-12.,3.14475459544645));
#545=CARTESIAN_POINT('',(21.8243639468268,-12.,3.45027074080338));
#546=CARTESIAN_POINT('',(23.0331444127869,-12.,4.06562299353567));
#547=CARTESIAN_POINT('',(23.636364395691,-12.,4.37545829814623));
#548=CARTESIAN_POINT('',(24.8409400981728,-12.,4.99872415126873));
#549=CARTESIAN_POINT('',(25.4422958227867,-12.,5.31215469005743));
#550=CARTESIAN_POINT('',(27.1254633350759,-12.,6.19473158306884));
#551=CARTESIAN_POINT('',(28.2055235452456,-12.,6.7672178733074));
#552=CARTESIAN_POINT('',(30.3619311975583,-12.,7.91925803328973));
#553=CARTESIAN_POINT('',(31.4382784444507,-12.,8.49881226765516));
#554=CARTESIAN_POINT('',(33.584834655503,-12.,9.66146627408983));
#555=CARTESIAN_POINT('',(34.6550523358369,-12.,10.2445499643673));
#556=CARTESIAN_POINT('',(36.2586680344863,-12.,11.1222102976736));
#557=CARTESIAN_POINT('',(36.7929031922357,-12.,11.4152594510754));
#558=CARTESIAN_POINT('',(37.8608740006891,-12.,12.0022649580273));
#559=CARTESIAN_POINT('',(38.3946096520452,-12.,12.2962213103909));
#560=CARTESIAN_POINT('',(38.9281254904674,-12.,12.5905761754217));
#561=B_SPLINE_CURVE_WITH_KNOTS('',3,(#485,#486,#487,#488,#489,#490,#491,#492,#493,#494,#495,
#496,#497,#498,#499,#500,#501,#502,#503,#504,#505,#506,#507,#508,#509,#510,#511,#512,#513,#514,
#515,#516,#517,#518,#519,#520,#521,#522,#523,#524,#525,#526,#527,#528,#529,#530,#531,#532,#533,
#534,#535,#536,#537,#538,#539,#540,#541,#542,#543,#544,#545,#546,#547,#548,#549,#550,#551,#552,
#553,#554,#555,#556,#557,#558,#559,#560),.UNSPECIFIED.,.F.,.F.,(4,2,2,2,2,2,2,2,2,2,2,2,2,2,2,2,
2,2,2,2,2,2,2,2,2,2,2,2,2,2,2,2,2,2,2,2,2,4),(0.,0.875574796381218,1.7511582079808,
3.50257929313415,5.2633676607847,7.02407385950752,8.84204683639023,10.6602219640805,
12.4747187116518,14.2886497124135,15.190737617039,16.0928074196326,16.9948591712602,
17.8968753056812,18.7869578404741,19.6770253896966,20.5671012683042,21.4572194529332,
22.7004447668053,23.9438339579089,26.4319090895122,27.7047859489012,28.9776720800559,
30.2501644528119,31.5226327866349,33.5537333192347,35.5850206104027,37.6169661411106,
39.648844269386,41.6836056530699,43.7183807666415,45.7527826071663,47.7871789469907,
51.4543492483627,55.1217095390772,58.7779483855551,60.6059425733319,62.4339343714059),.UNSPECIFIED.);
#562=CARTESIAN_POINT('',(6.92820323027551,-12.,-2.92820323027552));
#563=VERTEX_POINT('',#562);
#564=CARTESIAN_POINT('',(0.,-12.,-4.));
#565=VERTEX_POINT('',#564);
#566=EDGE_CURVE('E165',#563,#565,#561,.F.);
#567=ORIENTED_EDGE('',*,*,#566,.F.);
#568=DIRECTION('',(0.,0.,-1.));
#569=VECTOR('',#568,1.);
#570=CARTESIAN_POINT('',(6.92820323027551,-12.,4.));
#571=LINE('',#570,#569);
#572=CARTESIAN_POINT('',(6.92820323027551,-12.,2.92820323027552));
#573=VERTEX_POINT('',#572);
#574=EDGE_CURVE('E249',#573,#563,#571,.T.);
#575=ORIENTED_EDGE('',*,*,#574,.F.);
#576=CARTESIAN_POINT('',(-18.7085127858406,-12.,-1.90415756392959));
#577=CARTESIAN_POINT('',(-18.4460090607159,-12.,-1.77659054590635));
#578=CARTESIAN_POINT('',(-18.1831999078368,-12.,-1.64965232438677));
#579=CARTESIAN_POINT('',(-17.6569070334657,-12.,-1.39717571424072));
#580=CARTESIAN_POINT('',(-17.3934233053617,-12.,-1.27163733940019));
#581=CARTESIAN_POINT('',(-16.6017958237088,-12.,-0.897302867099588));
#582=CARTESIAN_POINT('',(-16.0725519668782,-12.,-0.650824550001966));
#583=CARTESIAN_POINT('',(-15.007722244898,-12.,-0.164215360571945));
#584=CARTESIAN_POINT('',(-14.4721175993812,-12.,0.0758745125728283));
#585=CARTESIAN_POINT('',(-13.3966823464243,-12.,0.546361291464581));
#586=CARTESIAN_POINT('',(-12.8568519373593,-12.,0.776758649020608));
#587=CARTESIAN_POINT('',(-11.7544580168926,-12.,1.23259581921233));
#588=CARTESIAN_POINT('',(-11.1917261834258,-12.,1.45763065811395));
#589=CARTESIAN_POINT('',(-10.0597119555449,-12.,1.89090699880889));
#590=CARTESIAN_POINT('',(-9.49042883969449,-12.,2.09914663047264));
#591=CARTESIAN_POINT('',(-8.34545795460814,-12.,2.49343583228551));
#592=CARTESIAN_POINT('',(-7.76978547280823,-12.,2.67952944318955));
#593=CARTESIAN_POINT('',(-6.61012992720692,-12.,3.023632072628));
#594=CARTESIAN_POINT('',(-6.02614951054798,-12.,3.1816498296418));
#595=CARTESIAN_POINT('',(-5.14541828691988,-12.,3.3915280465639));
#596=CARTESIAN_POINT('',(-4.85184995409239,-12.,3.45682212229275));
#597=CARTESIAN_POINT('',(-4.26268919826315,-12.,3.57758690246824));
#598=CARTESIAN_POINT('',(-3.96709681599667,-12.,3.63305780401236));
#599=CARTESIAN_POINT('',(-3.37408559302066,-12.,3.73320305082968));
#600=CARTESIAN_POINT('',(-3.07666678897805,-12.,3.77787761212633));
#601=CARTESIAN_POINT('',(-2.48030879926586,-12.,3.85554301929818));
#602=CARTESIAN_POINT('',(-2.18136967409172,-12.,3.88853432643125));
#603=CARTESIAN_POINT('',(-1.58633736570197,-12.,3.9417583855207));
#604=CARTESIAN_POINT('',(-1.29025885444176,-12.,3.96215415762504));
#605=CARTESIAN_POINT('',(-0.697504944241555,-12.,3.99040145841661));
#606=CARTESIAN_POINT('',(-0.400829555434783,-12.,3.9982531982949));
#607=CARTESIAN_POINT('',(0.192590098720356,-12.,4.00122522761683));
#608=CARTESIAN_POINT('',(0.489334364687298,-12.,3.99634539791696));
#609=CARTESIAN_POINT('',(1.08235044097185,-12.,3.97397458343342));
#610=CARTESIAN_POINT('',(1.37862222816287,-12.,3.95648299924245));
#611=CARTESIAN_POINT('',(2.08755229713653,-12.,3.89991202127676));
#612=CARTESIAN_POINT('',(2.49975691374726,-12.,3.85502143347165));
#613=CARTESIAN_POINT('',(3.32115295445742,-12.,3.74325294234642));
#614=CARTESIAN_POINT('',(3.73034397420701,-12.,3.676372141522));
#615=CARTESIAN_POINT('',(4.95289147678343,-12.,3.44628715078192));
#616=CARTESIAN_POINT('',(5.76078996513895,-12.,3.25367949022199));
#617=CARTESIAN_POINT('',(6.96921318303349,-12.,2.91902105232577));
#618=CARTESIAN_POINT('',(7.37598411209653,-12.,2.79822311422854));
#619=CARTESIAN_POINT('',(8.18557519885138,-12.,2.54392558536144));
#620=CARTESIAN_POINT('',(8.58839532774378,-12.,2.41042590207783));
#621=CARTESIAN_POINT('',(9.39021237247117,-12.,2.13288017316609));
#622=CARTESIAN_POINT('',(9.7892104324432,-12.,1.98883740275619));
#623=CARTESIAN_POINT('',(10.5838863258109,-12.,1.69191619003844));
#624=CARTESIAN_POINT('',(10.9795642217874,-12.,1.53903791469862));
#625=CARTESIAN_POINT('',(12.0030149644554,-12.,1.13257010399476));
#626=CARTESIAN_POINT('',(12.6285198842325,-12.,0.873276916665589));
#627=CARTESIAN_POINT('',(13.8734735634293,-12.,0.340490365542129));
#628=CARTESIAN_POINT('',(14.4929217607,-12.,0.0669956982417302));
#629=CARTESIAN_POINT('',(15.7270740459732,-12.,-0.490985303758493));
#630=CARTESIAN_POINT('',(16.3417765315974,-12.,-0.775475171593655));
#631=CARTESIAN_POINT('',(17.5671457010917,-12.,-1.35294000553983));
#632=CARTESIAN_POINT('',(18.1778125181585,-12.,-1.6459146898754));
#633=CARTESIAN_POINT('',(19.3967367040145,-12.,-2.23899938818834));
#634=CARTESIAN_POINT('',(20.0049894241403,-12.,-2.53911893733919));
#635=CARTESIAN_POINT('',(21.218803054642,-12.,-3.14475459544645));
#636=CARTESIAN_POINT('',(21.8243639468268,-12.,-3.45027074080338));
#637=CARTESIAN_POINT('',(23.0331444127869,-12.,-4.06562299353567));
#638=CARTESIAN_POINT('',(23.636364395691,-12.,-4.37545829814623));
#639=CARTESIAN_POINT('',(24.8409400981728,-12.,-4.99872415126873));
#640=CARTESIAN_POINT('',(25.4422958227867,-12.,-5.31215469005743));
#641=CARTESIAN_POINT('',(27.1254633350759,-12.,-6.19473158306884));
#642=CARTESIAN_POINT('',(28.2055235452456,-12.,-6.7672178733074));
#643=CARTESIAN_POINT('',(30.3619311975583,-12.,-7.91925803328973));
#644=CARTESIAN_POINT('',(31.4382784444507,-12.,-8.49881226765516));
#645=CARTESIAN_POINT('',(33.584834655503,-12.,-9.66146627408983));
#646=CARTESIAN_POINT('',(34.6550523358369,-12.,-10.2445499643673));
#647=CARTESIAN_POINT('',(36.2586680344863,-12.,-11.1222102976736));
#648=CARTESIAN_POINT('',(36.7929031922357,-12.,-11.4152594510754));
#649=CARTESIAN_POINT('',(37.8608740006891,-12.,-12.0022649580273));
#650=CARTESIAN_POINT('',(38.3946096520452,-12.,-12.2962213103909));
#651=CARTESIAN_POINT('',(38.9281254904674,-12.,-12.5905761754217));
#652=B_SPLINE_CURVE_WITH_KNOTS('',3,(#576,#577,#578,#579,#580,#581,#582,#583,#584,#585,#586,
#587,#588,#589,#590,#591,#592,#593,#594,#595,#596,#597,#598,#599,#600,#601,#602,#603,#604,#605,
#606,#607,#608,#609,#610,#611,#612,#613,#614,#615,#616,#617,#618,#619,#620,#621,#622,#623,#624,
#625,#626,#627,#628,#629,#630,#631,#632,#633,#634,#635,#636,#637,#638,#639,#640,#641,#642,#643,
#644,#645,#646,#647,#648,#649,#650,#651),.UNSPECIFIED.,.F.,.F.,(4,2,2,2,2,2,2,2,2,2,2,2,2,2,2,2,
2,2,2,2,2,2,2,2,2,2,2,2,2,2,2,2,2,2,2,2,2,4),(0.,0.875574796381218,1.7511582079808,
3.50257929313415,5.2633676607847,7.02407385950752,8.84204683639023,10.6602219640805,
12.4747187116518,14.2886497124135,15.190737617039,16.0928074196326,16.9948591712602,
17.8968753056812,18.7869578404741,19.6770253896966,20.5671012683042,21.4572194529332,
22.7004447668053,23.9438339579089,26.4319090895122,27.7047859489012,28.9776720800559,
30.2501644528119,31.5226327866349,33.5537333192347,35.5850206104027,37.6169661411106,
39.648844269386,41.6836056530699,43.7183807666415,45.7527826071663,47.7871789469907,
51.4543492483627,55.1217095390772,58.7779483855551,60.6059425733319,62.4339343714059),.UNSPECIFIED.);
#653=CARTESIAN_POINT('',(0.,-12.,4.));
#654=VERTEX_POINT('',#653);
#655=EDGE_CURVE('E298',#654,#573,#652,.T.);
#656=ORIENTED_EDGE('',*,*,#655,.F.);
#657=EDGE_CURVE('E301',#436,#654,#652,.T.);
#658=ORIENTED_EDGE('',*,*,#657,.F.);
#659=ORIENTED_EDGE('',*,*,#437,.T.);
#660=EDGE_CURVE('E140',#565,#426,#561,.F.);
#661=ORIENTED_EDGE('',*,*,#660,.F.);
#662=EDGE_LOOP('',(#567,#575,#656,#658,#659,#661));
#663=FACE_BOUND('',#662,.T.);
#664=ADVANCED_FACE('F300',(#663),#484,.F.);
#665=CARTESIAN_POINT('',(6.92820323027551,-12.,4.));
#666=DIRECTION('',(-0.866025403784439,0.5,0.));
#667=DIRECTION('',(-0.5,-0.866025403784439,0.));
#668=AXIS2_PLACEMENT_3D('',#665,#666,#667);
#669=PLANE('',#668);
#670=CARTESIAN_POINT('',(13.8565219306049,0.000199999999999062,-2.92813656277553));
#671=CARTESIAN_POINT('',(13.7042251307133,-0.263585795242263,-3.01605036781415));
#672=CARTESIAN_POINT('',(13.5513604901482,-0.528355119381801,-3.09997400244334));
#673=CARTESIAN_POINT('',(13.244405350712,-1.06001701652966,-3.25873378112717));
#674=CARTESIAN_POINT('',(13.0903144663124,-1.32691025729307,-3.33356693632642));
#675=CARTESIAN_POINT('',(12.6255589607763,-2.13189040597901,-3.54298246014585));
#676=CARTESIAN_POINT('',(12.3130596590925,-2.6731550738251,-3.66209676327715));
#677=CARTESIAN_POINT('',(11.8454187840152,-3.483132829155,-3.80176893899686));
#678=CARTESIAN_POINT('',(11.6916742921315,-3.74942610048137,-3.84155620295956));
#679=CARTESIAN_POINT('',(11.3834734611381,-4.28324559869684,-3.90827663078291));
#680=CARTESIAN_POINT('',(11.2290171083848,-4.55077184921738,-3.93520954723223));
#681=CARTESIAN_POINT('',(10.9198468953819,-5.08627036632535,-3.97553140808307));
#682=CARTESIAN_POINT('',(10.7651335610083,-5.35424172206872,-3.98893644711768));
#683=CARTESIAN_POINT('',(10.4555635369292,-5.89043273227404,-4.00191690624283));
#684=CARTESIAN_POINT('',(10.3007068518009,-6.15865237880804,-4.00149275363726));
#685=CARTESIAN_POINT('',(10.0112020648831,-6.6600893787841,-3.98777998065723));
#686=CARTESIAN_POINT('',(9.87653331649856,-6.89334249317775,-3.97616401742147));
#687=CARTESIAN_POINT('',(9.60750555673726,-7.35931224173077,-3.94269199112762));
#688=CARTESIAN_POINT('',(9.47314656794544,-7.59202883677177,-3.92083520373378));
#689=CARTESIAN_POINT('',(9.2048113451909,-8.05679907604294,-3.86726258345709));
#690=CARTESIAN_POINT('',(9.07083551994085,-8.288852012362,-3.83553860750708));
#691=CARTESIAN_POINT('',(8.80351197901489,-8.75186996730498,-3.76278822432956));
#692=CARTESIAN_POINT('',(8.67016430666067,-8.98283491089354,-3.7217611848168));
#693=CARTESIAN_POINT('',(8.2653799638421,-9.68394195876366,-3.5836883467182));
#694=CARTESIAN_POINT('',(7.99511549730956,-10.1520537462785,-3.47287511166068));
#695=CARTESIAN_POINT('',(7.45861659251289,-11.0812971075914,-3.22137423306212));
#696=CARTESIAN_POINT('',(7.19237528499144,-11.5424405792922,-3.08074565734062));
#697=CARTESIAN_POINT('',(6.92808776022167,-12.0002,-2.92813656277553));
#698=B_SPLINE_CURVE_WITH_KNOTS('',3,(#670,#671,#672,#673,#674,#675,#676,#677,#678,#679,#680,
#681,#682,#683,#684,#685,#686,#687,#688,#689,#690,#691,#692,#693,#694,#695,#696,#697),
.UNSPECIFIED.,.F.,.F.,(4,2,2,2,2,2,2,2,2,2,2,2,2,4),(0.,0.951004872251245,1.90232158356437,
3.80900466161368,4.7389455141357,5.66890426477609,6.59775529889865,7.5265776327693,
8.33514643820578,9.14377244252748,9.95306755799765,10.7624176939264,12.4167102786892,
14.0677556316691),.UNSPECIFIED.);
#699=CARTESIAN_POINT('',(10.3923048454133,-6.,-4.));
#700=VERTEX_POINT('',#699);
#701=EDGE_CURVE('E147',#109,#700,#698,.T.);
#702=ORIENTED_EDGE('',*,*,#701,.F.);
#703=ORIENTED_EDGE('',*,*,#110,.F.);
#704=CARTESIAN_POINT('',(6.92808776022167,-12.0002,2.92813656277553));
#705=CARTESIAN_POINT('',(7.08038456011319,-11.7364142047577,3.01605036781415));
#706=CARTESIAN_POINT('',(7.23324920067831,-11.4716448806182,3.09997400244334));
#707=CARTESIAN_POINT('',(7.5402043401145,-10.9399829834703,3.25873378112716));
#708=CARTESIAN_POINT('',(7.69429522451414,-10.6730897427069,3.33356693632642));
#709=CARTESIAN_POINT('',(8.15905073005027,-9.86810959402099,3.54298246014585));
#710=CARTESIAN_POINT('',(8.47155003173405,-9.3268449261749,3.66209676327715));
#711=CARTESIAN_POINT('',(8.93919090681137,-8.51686717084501,3.80176893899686));
#712=CARTESIAN_POINT('',(9.09293539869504,-8.25057389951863,3.84155620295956));
#713=CARTESIAN_POINT('',(9.40113622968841,-7.71675440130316,3.90827663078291));
#714=CARTESIAN_POINT('',(9.55559258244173,-7.44922815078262,3.93520954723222));
#715=CARTESIAN_POINT('',(9.86476279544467,-6.91372963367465,3.97553140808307));
#716=CARTESIAN_POINT('',(10.0194761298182,-6.64575827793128,3.98893644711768));
#717=CARTESIAN_POINT('',(10.3290461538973,-6.10956726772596,4.00191690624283));
#718=CARTESIAN_POINT('',(10.4839028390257,-5.84134762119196,4.00149275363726));
#719=CARTESIAN_POINT('',(10.7734076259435,-5.3399106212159,3.98777998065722));
#720=CARTESIAN_POINT('',(10.908076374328,-5.10665750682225,3.97616401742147));
#721=CARTESIAN_POINT('',(11.1771041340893,-4.64068775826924,3.94269199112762));
#722=CARTESIAN_POINT('',(11.3114631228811,-4.40797116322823,3.92083520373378));
#723=CARTESIAN_POINT('',(11.5797983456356,-3.94320092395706,3.86726258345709));
#724=CARTESIAN_POINT('',(11.7137741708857,-3.711147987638,3.83553860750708));
#725=CARTESIAN_POINT('',(11.9810977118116,-3.24813003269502,3.76278822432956));
#726=CARTESIAN_POINT('',(12.1144453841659,-3.01716508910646,3.7217611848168));
#727=CARTESIAN_POINT('',(12.5192297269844,-2.31605804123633,3.5836883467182));
#728=CARTESIAN_POINT('',(12.789494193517,-1.84794625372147,3.47287511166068));
#729=CARTESIAN_POINT('',(13.3259930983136,-0.918702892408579,3.22137423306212));
#730=CARTESIAN_POINT('',(13.5922344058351,-0.457559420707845,3.08074565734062));
#731=CARTESIAN_POINT('',(13.8565219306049,0.000199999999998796,2.92813656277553));
#732=B_SPLINE_CURVE_WITH_KNOTS('',3,(#704,#705,#706,#707,#708,#709,#710,#711,#712,#713,#714,
#715,#716,#717,#718,#719,#720,#721,#722,#723,#724,#725,#726,#727,#728,#729,#730,#731),
.UNSPECIFIED.,.F.,.F.,(4,2,2,2,2,2,2,2,2,2,2,2,2,4),(0.,0.951004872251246,1.90232158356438,
3.80900466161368,4.7389455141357,5.66890426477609,6.59775529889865,7.5265776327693,
8.33514643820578,9.14377244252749,9.95306755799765,10.7624176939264,12.4167102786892,
14.0677556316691),.UNSPECIFIED.);
#733=CARTESIAN_POINT('',(10.3923048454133,-6.,4.));
#734=VERTEX_POINT('',#733);
#735=EDGE_CURVE('E311',#734,#101,#732,.T.);
#736=ORIENTED_EDGE('',*,*,#735,.F.);
#737=EDGE_CURVE('E307',#573,#734,#732,.T.);
#738=ORIENTED_EDGE('',*,*,#737,.F.);
#739=ORIENTED_EDGE('',*,*,#574,.T.);
#740=EDGE_CURVE('E157',#700,#563,#698,.T.);
#741=ORIENTED_EDGE('',*,*,#740,.F.);
#742=EDGE_LOOP('',(#702,#703,#736,#738,#739,#741));
#743=FACE_BOUND('',#742,.T.);
#744=ADVANCED_FACE('F324',(#743),#669,.F.);
#745=CARTESIAN_POINT('',(0.,0.,4.));
#746=DIRECTION('',(0.,0.,-1.));
#747=DIRECTION('',(-1.,0.,0.));
#748=AXIS2_PLACEMENT_3D('',#745,#746,#747);
#749=CONICAL_SURFACE('',#748,12.,1.0471975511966);
#750=ORIENTED_EDGE('',*,*,#102,.T.);
#751=CARTESIAN_POINT('',(0.,0.,4.));
#752=DIRECTION('',(0.,0.,1.));
#753=DIRECTION('',(1.,0.,0.));
#754=AXIS2_PLACEMENT_3D('',#751,#752,#753);
#755=CIRCLE('',#754,12.);
#756=EDGE_CURVE('E266',#734,#97,#755,.T.);
#757=ORIENTED_EDGE('',*,*,#756,.F.);
#758=ORIENTED_EDGE('',*,*,#735,.T.);
#759=EDGE_LOOP('',(#750,#757,#758));
#760=FACE_BOUND('',#759,.T.);
#761=ADVANCED_FACE('F195',(#760),#749,.T.);
#762=ORIENTED_EDGE('',*,*,#655,.T.);
#763=ORIENTED_EDGE('',*,*,#737,.T.);
#764=EDGE_CURVE('E269',#654,#734,#755,.T.);
#765=ORIENTED_EDGE('',*,*,#764,.F.);
#766=EDGE_LOOP('',(#762,#763,#765));
#767=FACE_BOUND('',#766,.T.);
#768=ADVANCED_FACE('F370',(#767),#749,.T.);
#769=ORIENTED_EDGE('',*,*,#470,.T.);
#770=ORIENTED_EDGE('',*,*,#657,.T.);
#771=EDGE_CURVE('E275',#469,#654,#755,.T.);
#772=ORIENTED_EDGE('',*,*,#771,.F.);
#773=EDGE_LOOP('',(#769,#770,#772));
#774=FACE_BOUND('',#773,.T.);
#775=ADVANCED_FACE('F379',(#774),#749,.T.);
#776=ORIENTED_EDGE('',*,*,#381,.T.);
#777=ORIENTED_EDGE('',*,*,#472,.T.);
#778=EDGE_CURVE('E278',#380,#469,#755,.T.);
#779=ORIENTED_EDGE('',*,*,#778,.F.);
#780=EDGE_LOOP('',(#776,#777,#779));
#781=FACE_BOUND('',#780,.T.);
#782=ADVANCED_FACE('F386',(#781),#749,.T.);
#783=ORIENTED_EDGE('',*,*,#292,.T.);
#784=ORIENTED_EDGE('',*,*,#383,.T.);
#785=EDGE_CURVE('E153',#291,#380,#755,.T.);
#786=ORIENTED_EDGE('',*,*,#785,.F.);
#787=EDGE_LOOP('',(#783,#784,#786));
#788=FACE_BOUND('',#787,.T.);
#789=ADVANCED_FACE('F393',(#788),#749,.T.);
#790=ORIENTED_EDGE('',*,*,#98,.T.);
#791=ORIENTED_EDGE('',*,*,#294,.T.);
#792=CARTESIAN_POINT('',(0.,0.,4.));
#793=DIRECTION('',(0.,0.,1.));
#794=DIRECTION('',(1.,0.,0.));
#795=AXIS2_PLACEMENT_3D('',#792,#793,#794);
#796=CIRCLE('',#795,12.);
#797=EDGE_CURVE('E527',#97,#291,#796,.T.);
#798=ORIENTED_EDGE('',*,*,#797,.F.);
#799=EDGE_LOOP('',(#790,#791,#798));
#800=FACE_BOUND('',#799,.T.);
#801=ADVANCED_FACE('F372',(#800),#749,.T.);
#802=CARTESIAN_POINT('',(6.92820323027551,12.,4.));
#803=DIRECTION('',(0.,0.,1.));
#804=DIRECTION('',(1.,0.,0.));
#805=AXIS2_PLACEMENT_3D('',#802,#803,#804);
#806=PLANE('',#805);
#807=CARTESIAN_POINT('',(0.,0.,4.));
#808=DIRECTION('',(0.,0.,1.));
#809=DIRECTION('',(1.,0.,0.));
#810=AXIS2_PLACEMENT_3D('',#807,#808,#809);
#811=CIRCLE('',#810,7.);
#812=CARTESIAN_POINT('',(7.,0.,4.));
#813=VERTEX_POINT('',#812);
#814=EDGE_CURVE('E519',#813,#813,#811,.T.);
#815=ORIENTED_EDGE('',*,*,#814,.F.);
#816=EDGE_LOOP('',(#815));
#817=FACE_BOUND('',#816,.T.);
#818=ORIENTED_EDGE('',*,*,#756,.T.);
#819=ORIENTED_EDGE('',*,*,#797,.T.);
#820=ORIENTED_EDGE('',*,*,#785,.T.);
#821=ORIENTED_EDGE('',*,*,#778,.T.);
#822=ORIENTED_EDGE('',*,*,#771,.T.);
#823=ORIENTED_EDGE('',*,*,#764,.T.);
#824=EDGE_LOOP('',(#818,#819,#820,#821,#822,#823));
#825=FACE_BOUND('',#824,.T.);
#826=ADVANCED_FACE('F292',(#817,#825),#806,.T.);
#827=CARTESIAN_POINT('',(0.,0.,-4.));
#828=DIRECTION('',(0.,0.,1.));
#829=DIRECTION('',(-1.,0.,0.));
#830=AXIS2_PLACEMENT_3D('',#827,#828,#829);
#831=CONICAL_SURFACE('',#830,12.,1.0471975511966);
#832=ORIENTED_EDGE('',*,*,#112,.T.);
#833=ORIENTED_EDGE('',*,*,#701,.T.);
#834=CARTESIAN_POINT('',(0.,0.,-4.));
#835=DIRECTION('',(0.,0.,1.));
#836=DIRECTION('',(1.,0.,0.));
#837=AXIS2_PLACEMENT_3D('',#834,#835,#836);
#838=CIRCLE('',#837,12.);
#839=EDGE_CURVE('E41',#700,#56,#838,.T.);
#840=ORIENTED_EDGE('',*,*,#839,.T.);
#841=EDGE_LOOP('',(#832,#833,#840));
#842=FACE_BOUND('',#841,.T.);
#843=ADVANCED_FACE('F145',(#842),#831,.T.);
#844=ORIENTED_EDGE('',*,*,#566,.T.);
#845=EDGE_CURVE('E152',#565,#700,#838,.T.);
#846=ORIENTED_EDGE('',*,*,#845,.T.);
#847=ORIENTED_EDGE('',*,*,#740,.T.);
#848=EDGE_LOOP('',(#844,#846,#847));
#849=FACE_BOUND('',#848,.T.);
#850=ADVANCED_FACE('F193',(#849),#831,.T.);
#851=ORIENTED_EDGE('',*,*,#429,.T.);
#852=EDGE_CURVE('E546',#428,#565,#838,.T.);
#853=ORIENTED_EDGE('',*,*,#852,.T.);
#854=ORIENTED_EDGE('',*,*,#660,.T.);
#855=EDGE_LOOP('',(#851,#853,#854));
#856=FACE_BOUND('',#855,.T.);
#857=ADVANCED_FACE('F192',(#856),#831,.T.);
#858=ORIENTED_EDGE('',*,*,#340,.T.);
#859=EDGE_CURVE('E47',#339,#428,#838,.T.);
#860=ORIENTED_EDGE('',*,*,#859,.T.);
#861=ORIENTED_EDGE('',*,*,#475,.T.);
#862=EDGE_LOOP('',(#858,#860,#861));
#863=FACE_BOUND('',#862,.T.);
#864=ADVANCED_FACE('F186',(#863),#831,.T.);
#865=ORIENTED_EDGE('',*,*,#386,.T.);
#866=ORIENTED_EDGE('',*,*,#203,.T.);
#867=EDGE_CURVE('E11',#202,#339,#838,.T.);
#868=ORIENTED_EDGE('',*,*,#867,.T.);
#869=EDGE_LOOP('',(#865,#866,#868));
#870=FACE_BOUND('',#869,.T.);
#871=ADVANCED_FACE('F191',(#870),#831,.T.);
#872=ORIENTED_EDGE('',*,*,#297,.T.);
#873=ORIENTED_EDGE('',*,*,#57,.T.);
#874=CARTESIAN_POINT('',(0.,0.,-4.));
#875=DIRECTION('',(0.,0.,1.));
#876=DIRECTION('',(1.,0.,0.));
#877=AXIS2_PLACEMENT_3D('',#874,#875,#876);
#878=CIRCLE('',#877,12.);
#879=EDGE_CURVE('E131',#56,#202,#878,.T.);
#880=ORIENTED_EDGE('',*,*,#879,.T.);
#881=EDGE_LOOP('',(#872,#873,#880));
#882=FACE_BOUND('',#881,.T.);
#883=ADVANCED_FACE('F129',(#882),#831,.T.);
#884=CARTESIAN_POINT('',(6.92820323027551,12.,-4.));
#885=DIRECTION('',(0.,0.,1.));
#886=DIRECTION('',(1.,0.,0.));
#887=AXIS2_PLACEMENT_3D('',#884,#885,#886);
#888=PLANE('',#887);
#889=CARTESIAN_POINT('',(0.,0.,-4.));
#890=DIRECTION('',(0.,0.,1.));
#891=DIRECTION('',(1.,0.,0.));
#892=AXIS2_PLACEMENT_3D('',#889,#890,#891);
#893=CIRCLE('',#892,7.);
#894=CARTESIAN_POINT('',(7.,0.,-4.));
#895=VERTEX_POINT('',#894);
#896=EDGE_CURVE('E158',#895,#895,#893,.T.);
#897=ORIENTED_EDGE('',*,*,#896,.T.);
#898=EDGE_LOOP('',(#897));
#899=FACE_BOUND('',#898,.T.);
#900=ORIENTED_EDGE('',*,*,#879,.F.);
#901=ORIENTED_EDGE('',*,*,#839,.F.);
#902=ORIENTED_EDGE('',*,*,#845,.F.);
#903=ORIENTED_EDGE('',*,*,#852,.F.);
#904=ORIENTED_EDGE('',*,*,#859,.F.);
#905=ORIENTED_EDGE('',*,*,#867,.F.);
#906=EDGE_LOOP('',(#900,#901,#902,#903,#904,#905));
#907=FACE_BOUND('',#906,.T.);
#908=ADVANCED_FACE('F154',(#899,#907),#888,.F.);
#909=CARTESIAN_POINT('',(0.,0.,4.));
#910=DIRECTION('',(0.,0.,1.));
#911=DIRECTION('',(1.,0.,0.));
#912=AXIS2_PLACEMENT_3D('',#909,#910,#911);
#913=CYLINDRICAL_SURFACE('',#912,7.);
#914=ORIENTED_EDGE('',*,*,#896,.F.);
#915=EDGE_LOOP('',(#914));
#916=FACE_BOUND('',#915,.T.);
#917=ORIENTED_EDGE('',*,*,#814,.T.);
#918=EDGE_LOOP('',(#917));
#919=FACE_BOUND('',#918,.T.);
#920=ADVANCED_FACE('F194',(#916,#919),#913,.F.);
#921=CLOSED_SHELL('',(#116,#301,#390,#479,#664,#744,#761,#768,#775,#782,#789,#801,#826,#843,
#850,#857,#864,#871,#883,#908,#920));
#922=MANIFOLD_SOLID_BREP('B2',#921);
#923=ADVANCED_BREP_SHAPE_REPRESENTATION('',(#18,#922),#14);
#924=SHAPE_DEFINITION_REPRESENTATION(#9,#923);
ENDSEC;
END-ISO-10303-21;
